VERSION 5.7 ;
  NOWIREEXTENSIONATPIN ON ;
  DIVIDERCHAR "/" ;
  BUSBITCHARS "[]" ;
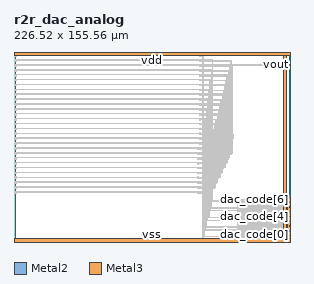
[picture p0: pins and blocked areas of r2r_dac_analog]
MACRO r2r_dac_analog
  CLASS BLOCK ;
  FOREIGN r2r_dac_analog ;
  ORIGIN 0.000 0.000 ;
  SIZE 226.520 BY 155.560 ;
  PIN dac_code[7]
    DIRECTION INPUT ;
    USE SIGNAL ;
    ANTENNAGATEAREA 11.020000 ;
    PORT
      LAYER Metal2 ;
        RECT 225.320 32.415 226.520 32.815 ;
    END
  END dac_code[7]
  PIN dac_code[6]
    DIRECTION INPUT ;
    USE SIGNAL ;
    ANTENNAGATEAREA 11.020000 ;
    PORT
      LAYER Metal2 ;
        RECT 225.320 28.465 226.520 28.865 ;
    END
  END dac_code[6]
  PIN dac_code[5]
    DIRECTION INPUT ;
    USE SIGNAL ;
    ANTENNAGATEAREA 11.020000 ;
    PORT
      LAYER Metal2 ;
        RECT 225.320 24.575 226.520 24.975 ;
    END
  END dac_code[5]
  PIN dac_code[4]
    DIRECTION INPUT ;
    USE SIGNAL ;
    ANTENNAGATEAREA 11.020000 ;
    PORT
      LAYER Metal2 ;
        RECT 225.320 20.625 226.520 21.025 ;
    END
  END dac_code[4]
  PIN dac_code[3]
    DIRECTION INPUT ;
    USE SIGNAL ;
    ANTENNAGATEAREA 11.020000 ;
    PORT
      LAYER Metal2 ;
        RECT 225.320 16.735 226.520 17.135 ;
    END
  END dac_code[3]
  PIN dac_code[2]
    DIRECTION INPUT ;
    USE SIGNAL ;
    ANTENNAGATEAREA 11.020000 ;
    PORT
      LAYER Metal2 ;
        RECT 225.320 12.785 226.520 13.185 ;
    END
  END dac_code[2]
  PIN dac_code[1]
    DIRECTION INPUT ;
    USE SIGNAL ;
    ANTENNAGATEAREA 11.020000 ;
    PORT
      LAYER Metal2 ;
        RECT 225.320 8.895 226.520 9.295 ;
    END
  END dac_code[1]
  PIN dac_code[0]
    DIRECTION INPUT ;
    USE SIGNAL ;
    ANTENNAGATEAREA 11.020000 ;
    PORT
      LAYER Metal2 ;
        RECT 225.320 4.945 226.520 5.345 ;
    END
  END dac_code[0]
  PIN vout
    DIRECTION INOUT ;
    USE SIGNAL ;
    PORT
      LAYER Metal2 ;
        RECT 225.320 144.810 226.520 145.210 ;
    END
  END vout
  PIN vdd
    DIRECTION INOUT ;
    USE POWER ;
    PORT
      LAYER Metal3 ;
        RECT 0.000 152.760 226.520 155.560 ;
    END
    PORT
      LAYER Metal3 ;
        RECT 220.520 6.320 223.220 152.760 ;
    END
  END vdd
  PIN vss
    DIRECTION INOUT ;
    USE GROUND ;
    PORT
      LAYER Metal3 ;
        RECT 0.000 0.000 226.520 2.800 ;
    END
    PORT
      LAYER Metal3 ;
        RECT 223.520 2.800 226.520 35.360 ;
    END
  END vss
  OBS
      LAYER Pwell ;
        RECT 183.130 32.800 220.950 34.990 ;
      LAYER Nwell ;
        RECT 183.130 28.480 220.950 32.800 ;
      LAYER Pwell ;
        RECT 183.130 24.960 220.950 28.480 ;
      LAYER Nwell ;
        RECT 183.130 20.640 220.950 24.960 ;
      LAYER Pwell ;
        RECT 183.130 17.120 220.950 20.640 ;
      LAYER Nwell ;
        RECT 183.130 12.800 220.950 17.120 ;
      LAYER Pwell ;
        RECT 183.130 9.280 220.950 12.800 ;
      LAYER Nwell ;
        RECT 183.130 4.960 220.950 9.280 ;
      LAYER Pwell ;
        RECT 183.130 2.770 220.950 4.960 ;
      LAYER Metal1 ;
        RECT 0.150 1.200 0.530 155.560 ;
        RECT 1.520 153.210 1.900 153.260 ;
        RECT 1.510 152.810 1.910 153.210 ;
        RECT 1.520 151.860 1.900 152.810 ;
        RECT 152.180 152.310 152.560 153.260 ;
        RECT 152.170 151.910 152.570 152.310 ;
        RECT 152.180 151.860 152.560 151.910 ;
        RECT 1.520 149.210 1.900 149.260 ;
        RECT 1.510 148.810 1.910 149.210 ;
        RECT 1.520 147.860 1.900 148.810 ;
        RECT 152.180 148.310 152.560 149.260 ;
        RECT 152.170 147.910 152.570 148.310 ;
        RECT 152.180 147.860 152.560 147.910 ;
        RECT 1.520 145.210 1.900 145.260 ;
        RECT 1.510 144.810 1.910 145.210 ;
        RECT 1.520 143.860 1.900 144.810 ;
        RECT 152.180 144.310 152.560 145.260 ;
        RECT 152.170 143.910 152.570 144.310 ;
        RECT 152.180 143.860 152.560 143.910 ;
        RECT 1.520 141.210 1.900 141.260 ;
        RECT 1.510 140.810 1.910 141.210 ;
        RECT 1.520 139.860 1.900 140.810 ;
        RECT 152.180 140.310 152.560 141.260 ;
        RECT 152.170 139.910 152.570 140.310 ;
        RECT 152.180 139.860 152.560 139.910 ;
        RECT 1.520 137.210 1.900 137.260 ;
        RECT 1.510 136.810 1.910 137.210 ;
        RECT 1.520 135.860 1.900 136.810 ;
        RECT 152.180 136.310 152.560 137.260 ;
        RECT 152.170 135.910 152.570 136.310 ;
        RECT 152.180 135.860 152.560 135.910 ;
        RECT 1.520 133.210 1.900 133.260 ;
        RECT 1.510 132.810 1.910 133.210 ;
        RECT 1.520 131.860 1.900 132.810 ;
        RECT 152.180 132.310 152.560 133.260 ;
        RECT 152.170 131.910 152.570 132.310 ;
        RECT 152.180 131.860 152.560 131.910 ;
        RECT 1.520 129.210 1.900 129.260 ;
        RECT 1.510 128.810 1.910 129.210 ;
        RECT 1.520 127.860 1.900 128.810 ;
        RECT 152.180 128.310 152.560 129.260 ;
        RECT 152.170 127.910 152.570 128.310 ;
        RECT 152.180 127.860 152.560 127.910 ;
        RECT 1.520 125.210 1.900 125.260 ;
        RECT 1.510 124.810 1.910 125.210 ;
        RECT 1.520 123.860 1.900 124.810 ;
        RECT 152.180 124.310 152.560 125.260 ;
        RECT 152.170 123.910 152.570 124.310 ;
        RECT 152.180 123.860 152.560 123.910 ;
        RECT 1.520 121.210 1.900 121.260 ;
        RECT 1.510 120.810 1.910 121.210 ;
        RECT 1.520 119.860 1.900 120.810 ;
        RECT 152.180 120.310 152.560 121.260 ;
        RECT 152.170 119.910 152.570 120.310 ;
        RECT 152.180 119.860 152.560 119.910 ;
        RECT 1.520 117.210 1.900 117.260 ;
        RECT 1.510 116.810 1.910 117.210 ;
        RECT 1.520 115.860 1.900 116.810 ;
        RECT 152.180 116.310 152.560 117.260 ;
        RECT 152.170 115.910 152.570 116.310 ;
        RECT 152.180 115.860 152.560 115.910 ;
        RECT 1.520 113.210 1.900 113.260 ;
        RECT 1.510 112.810 1.910 113.210 ;
        RECT 1.520 111.860 1.900 112.810 ;
        RECT 152.180 112.310 152.560 113.260 ;
        RECT 152.170 111.910 152.570 112.310 ;
        RECT 152.180 111.860 152.560 111.910 ;
        RECT 1.520 109.210 1.900 109.260 ;
        RECT 1.510 108.810 1.910 109.210 ;
        RECT 1.520 107.860 1.900 108.810 ;
        RECT 152.180 108.310 152.560 109.260 ;
        RECT 152.170 107.910 152.570 108.310 ;
        RECT 152.180 107.860 152.560 107.910 ;
        RECT 1.520 105.210 1.900 105.260 ;
        RECT 1.510 104.810 1.910 105.210 ;
        RECT 1.520 103.860 1.900 104.810 ;
        RECT 152.180 104.310 152.560 105.260 ;
        RECT 152.170 103.910 152.570 104.310 ;
        RECT 152.180 103.860 152.560 103.910 ;
        RECT 1.520 101.210 1.900 101.260 ;
        RECT 1.510 100.810 1.910 101.210 ;
        RECT 1.520 99.860 1.900 100.810 ;
        RECT 152.180 100.310 152.560 101.260 ;
        RECT 152.170 99.910 152.570 100.310 ;
        RECT 152.180 99.860 152.560 99.910 ;
        RECT 1.520 97.210 1.900 97.260 ;
        RECT 1.510 96.810 1.910 97.210 ;
        RECT 1.520 95.860 1.900 96.810 ;
        RECT 152.180 96.310 152.560 97.260 ;
        RECT 152.170 95.910 152.570 96.310 ;
        RECT 152.180 95.860 152.560 95.910 ;
        RECT 1.520 93.210 1.900 93.260 ;
        RECT 1.510 92.810 1.910 93.210 ;
        RECT 1.520 91.860 1.900 92.810 ;
        RECT 152.180 92.310 152.560 93.260 ;
        RECT 152.170 91.910 152.570 92.310 ;
        RECT 152.180 91.860 152.560 91.910 ;
        RECT 1.520 89.210 1.900 89.260 ;
        RECT 1.510 88.810 1.910 89.210 ;
        RECT 1.520 87.860 1.900 88.810 ;
        RECT 152.180 88.310 152.560 89.260 ;
        RECT 152.170 87.910 152.570 88.310 ;
        RECT 152.180 87.860 152.560 87.910 ;
        RECT 1.520 85.210 1.900 85.260 ;
        RECT 1.510 84.810 1.910 85.210 ;
        RECT 1.520 83.860 1.900 84.810 ;
        RECT 152.180 84.310 152.560 85.260 ;
        RECT 152.170 83.910 152.570 84.310 ;
        RECT 152.180 83.860 152.560 83.910 ;
        RECT 1.520 81.210 1.900 81.260 ;
        RECT 1.510 80.810 1.910 81.210 ;
        RECT 1.520 79.860 1.900 80.810 ;
        RECT 152.180 80.310 152.560 81.260 ;
        RECT 152.170 79.910 152.570 80.310 ;
        RECT 152.180 79.860 152.560 79.910 ;
        RECT 1.520 77.210 1.900 77.260 ;
        RECT 1.510 76.810 1.910 77.210 ;
        RECT 1.520 75.860 1.900 76.810 ;
        RECT 150.540 76.310 150.920 77.260 ;
        RECT 150.530 75.910 150.930 76.310 ;
        RECT 150.540 75.860 150.920 75.910 ;
        RECT 1.520 73.210 1.900 73.260 ;
        RECT 1.510 72.810 1.910 73.210 ;
        RECT 1.520 71.860 1.900 72.810 ;
        RECT 150.540 72.310 150.920 73.260 ;
        RECT 150.530 71.910 150.930 72.310 ;
        RECT 150.540 71.860 150.920 71.910 ;
        RECT 1.520 69.210 1.900 69.260 ;
        RECT 1.510 68.810 1.910 69.210 ;
        RECT 1.520 67.860 1.900 68.810 ;
        RECT 150.540 68.310 150.920 69.260 ;
        RECT 150.530 67.910 150.930 68.310 ;
        RECT 150.540 67.860 150.920 67.910 ;
        RECT 1.520 65.210 1.900 65.260 ;
        RECT 1.510 64.810 1.910 65.210 ;
        RECT 1.520 63.860 1.900 64.810 ;
        RECT 150.540 64.310 150.920 65.260 ;
        RECT 150.530 63.910 150.930 64.310 ;
        RECT 150.540 63.860 150.920 63.910 ;
        RECT 1.520 61.210 1.900 61.260 ;
        RECT 1.510 60.810 1.910 61.210 ;
        RECT 1.520 59.860 1.900 60.810 ;
        RECT 150.540 60.310 150.920 61.260 ;
        RECT 150.530 59.910 150.930 60.310 ;
        RECT 150.540 59.860 150.920 59.910 ;
        RECT 1.520 57.210 1.900 57.260 ;
        RECT 1.510 56.810 1.910 57.210 ;
        RECT 1.520 55.860 1.900 56.810 ;
        RECT 150.540 56.310 150.920 57.260 ;
        RECT 150.530 55.910 150.930 56.310 ;
        RECT 150.540 55.860 150.920 55.910 ;
        RECT 1.520 53.210 1.900 53.260 ;
        RECT 1.510 52.810 1.910 53.210 ;
        RECT 1.520 51.860 1.900 52.810 ;
        RECT 150.540 52.310 150.920 53.260 ;
        RECT 150.530 51.910 150.930 52.310 ;
        RECT 150.540 51.860 150.920 51.910 ;
        RECT 1.520 49.210 1.900 49.260 ;
        RECT 1.510 48.810 1.910 49.210 ;
        RECT 1.520 47.860 1.900 48.810 ;
        RECT 150.540 48.310 150.920 49.260 ;
        RECT 150.530 47.910 150.930 48.310 ;
        RECT 150.540 47.860 150.920 47.910 ;
        RECT 1.520 45.210 1.900 45.260 ;
        RECT 1.510 44.810 1.910 45.210 ;
        RECT 1.520 43.860 1.900 44.810 ;
        RECT 150.540 44.310 150.920 45.260 ;
        RECT 150.530 43.910 150.930 44.310 ;
        RECT 150.540 43.860 150.920 43.910 ;
        RECT 1.520 41.210 1.900 41.260 ;
        RECT 1.510 40.810 1.910 41.210 ;
        RECT 1.520 39.860 1.900 40.810 ;
        RECT 150.540 40.310 150.920 41.260 ;
        RECT 150.530 39.910 150.930 40.310 ;
        RECT 150.540 39.860 150.920 39.910 ;
        RECT 0.140 0.000 0.540 1.200 ;
        RECT 154.360 0.000 154.760 153.210 ;
        RECT 155.360 4.100 155.760 93.210 ;
        RECT 156.360 9.740 156.760 101.210 ;
        RECT 157.360 11.940 157.760 109.210 ;
        RECT 158.360 17.580 158.760 117.210 ;
        RECT 159.360 19.780 159.760 125.210 ;
        RECT 160.360 25.420 160.760 133.210 ;
        RECT 161.360 27.620 161.760 141.210 ;
        RECT 162.360 33.260 162.760 149.210 ;
        RECT 163.360 43.910 163.760 92.310 ;
        RECT 164.360 44.810 164.760 96.310 ;
        RECT 165.360 47.910 165.760 100.310 ;
        RECT 166.360 48.810 166.760 104.310 ;
        RECT 167.360 51.910 167.760 108.310 ;
        RECT 168.360 52.810 168.760 112.310 ;
        RECT 169.360 55.910 169.760 116.310 ;
        RECT 170.360 56.810 170.760 120.310 ;
        RECT 171.360 59.910 171.760 124.310 ;
        RECT 172.360 60.810 172.760 128.310 ;
        RECT 173.360 63.910 173.760 132.310 ;
        RECT 174.360 64.810 174.760 136.310 ;
        RECT 175.360 67.910 175.760 140.310 ;
        RECT 176.360 68.810 176.760 144.310 ;
        RECT 177.360 71.910 177.760 148.310 ;
        RECT 178.360 72.810 178.760 145.210 ;
        RECT 220.920 144.810 225.720 145.210 ;
        RECT 179.360 84.810 179.760 88.310 ;
        RECT 219.400 34.860 226.220 35.360 ;
        RECT 183.560 34.260 226.220 34.860 ;
        RECT 183.950 33.375 184.290 34.260 ;
        RECT 184.925 33.400 185.155 34.260 ;
        RECT 186.045 33.370 186.275 33.885 ;
        RECT 187.165 33.600 187.395 34.260 ;
        RECT 188.285 33.370 188.515 33.885 ;
        RECT 189.405 33.600 189.635 34.260 ;
        RECT 190.525 33.370 190.755 33.885 ;
        RECT 191.645 33.600 191.875 34.260 ;
        RECT 192.765 33.370 192.995 33.885 ;
        RECT 193.885 33.600 194.115 34.260 ;
        RECT 195.005 33.370 195.360 33.885 ;
        RECT 196.125 33.600 196.355 34.260 ;
        RECT 198.310 33.925 198.650 34.260 ;
        RECT 200.550 33.925 200.890 34.260 ;
        RECT 202.790 33.925 203.130 34.260 ;
        RECT 205.030 33.925 205.370 34.260 ;
        RECT 207.270 33.925 207.610 34.260 ;
        RECT 209.510 33.925 209.850 34.260 ;
        RECT 211.750 33.925 212.090 34.260 ;
        RECT 213.990 33.925 214.330 34.260 ;
        RECT 216.230 33.925 216.570 34.260 ;
        RECT 197.245 33.695 197.505 33.885 ;
        RECT 199.485 33.695 199.715 33.885 ;
        RECT 201.725 33.695 201.955 33.885 ;
        RECT 203.965 33.695 204.195 33.885 ;
        RECT 206.205 33.695 206.435 33.885 ;
        RECT 208.445 33.695 208.675 33.885 ;
        RECT 210.685 33.695 210.915 33.885 ;
        RECT 212.925 33.695 213.155 33.885 ;
        RECT 215.165 33.695 215.395 33.885 ;
        RECT 217.405 33.695 217.635 33.885 ;
        RECT 186.045 33.140 195.360 33.370 ;
        RECT 194.905 32.820 195.360 33.140 ;
        RECT 197.245 33.050 217.635 33.695 ;
        RECT 218.525 33.400 218.755 34.260 ;
        RECT 219.400 33.760 226.220 34.260 ;
        RECT 219.790 33.375 220.130 33.760 ;
        RECT 183.950 30.940 184.290 32.630 ;
        RECT 185.310 32.410 194.580 32.820 ;
        RECT 194.905 32.590 206.250 32.820 ;
        RECT 194.905 32.030 195.360 32.590 ;
        RECT 206.910 32.290 207.810 33.050 ;
        RECT 208.360 32.590 218.280 32.820 ;
        RECT 184.925 30.940 185.155 32.030 ;
        RECT 186.045 31.800 195.360 32.030 ;
        RECT 186.045 31.180 186.275 31.800 ;
        RECT 187.065 30.940 187.295 31.560 ;
        RECT 188.185 31.180 188.415 31.800 ;
        RECT 189.305 30.940 189.535 31.560 ;
        RECT 190.425 31.180 190.655 31.800 ;
        RECT 191.545 30.940 191.775 31.560 ;
        RECT 192.665 31.180 192.895 31.800 ;
        RECT 193.785 30.940 194.015 31.560 ;
        RECT 194.905 31.180 195.360 31.800 ;
        RECT 196.025 30.940 196.255 32.030 ;
        RECT 197.245 31.560 217.535 32.290 ;
        RECT 197.245 31.180 197.475 31.560 ;
        RECT 198.265 30.940 198.495 31.330 ;
        RECT 199.385 31.180 199.615 31.560 ;
        RECT 200.505 30.940 200.735 31.330 ;
        RECT 201.625 31.180 201.855 31.560 ;
        RECT 202.745 30.940 202.975 31.330 ;
        RECT 203.865 31.180 204.095 31.560 ;
        RECT 204.985 30.940 205.215 31.330 ;
        RECT 206.105 31.180 206.335 31.560 ;
        RECT 207.225 30.940 207.455 31.330 ;
        RECT 208.345 31.180 208.575 31.560 ;
        RECT 209.465 30.940 209.695 31.330 ;
        RECT 210.585 31.180 210.815 31.560 ;
        RECT 211.705 30.940 211.935 31.330 ;
        RECT 212.825 31.180 213.055 31.560 ;
        RECT 213.945 30.940 214.175 31.330 ;
        RECT 215.065 31.180 215.295 31.560 ;
        RECT 216.185 30.940 216.415 31.330 ;
        RECT 217.305 31.180 217.535 31.560 ;
        RECT 218.425 30.940 218.655 32.030 ;
        RECT 219.790 31.440 220.130 32.630 ;
        RECT 220.920 32.415 225.720 32.815 ;
        RECT 219.400 30.940 226.220 31.440 ;
        RECT 183.560 30.340 226.220 30.940 ;
        RECT 183.950 28.650 184.290 30.340 ;
        RECT 184.925 29.250 185.155 30.340 ;
        RECT 186.045 29.480 186.275 30.100 ;
        RECT 187.065 29.720 187.295 30.340 ;
        RECT 188.185 29.480 188.415 30.100 ;
        RECT 189.305 29.720 189.535 30.340 ;
        RECT 190.425 29.480 190.655 30.100 ;
        RECT 191.545 29.720 191.775 30.340 ;
        RECT 192.665 29.480 192.895 30.100 ;
        RECT 193.785 29.720 194.015 30.340 ;
        RECT 194.905 29.480 195.360 30.100 ;
        RECT 186.045 29.250 195.360 29.480 ;
        RECT 196.025 29.250 196.255 30.340 ;
        RECT 197.245 29.720 197.475 30.100 ;
        RECT 198.265 29.950 198.495 30.340 ;
        RECT 199.385 29.720 199.615 30.100 ;
        RECT 200.505 29.950 200.735 30.340 ;
        RECT 201.625 29.720 201.855 30.100 ;
        RECT 202.745 29.950 202.975 30.340 ;
        RECT 203.865 29.720 204.095 30.100 ;
        RECT 204.985 29.950 205.215 30.340 ;
        RECT 206.105 29.720 206.335 30.100 ;
        RECT 207.225 29.950 207.455 30.340 ;
        RECT 208.345 29.720 208.575 30.100 ;
        RECT 209.465 29.950 209.695 30.340 ;
        RECT 210.585 29.720 210.815 30.100 ;
        RECT 211.705 29.950 211.935 30.340 ;
        RECT 212.825 29.720 213.055 30.100 ;
        RECT 213.945 29.950 214.175 30.340 ;
        RECT 215.065 29.720 215.295 30.100 ;
        RECT 216.185 29.950 216.415 30.340 ;
        RECT 217.305 29.720 217.535 30.100 ;
        RECT 185.310 28.460 194.580 28.870 ;
        RECT 194.905 28.690 195.360 29.250 ;
        RECT 197.245 28.990 217.535 29.720 ;
        RECT 218.425 29.250 218.655 30.340 ;
        RECT 219.400 29.840 226.220 30.340 ;
        RECT 194.905 28.460 206.250 28.690 ;
        RECT 194.905 28.140 195.360 28.460 ;
        RECT 206.910 28.230 207.810 28.990 ;
        RECT 208.360 28.460 218.280 28.690 ;
        RECT 219.790 28.650 220.130 29.840 ;
        RECT 220.920 28.465 225.720 28.865 ;
        RECT 186.045 27.910 195.360 28.140 ;
        RECT 183.950 27.020 184.290 27.905 ;
        RECT 184.925 27.020 185.155 27.880 ;
        RECT 186.045 27.395 186.275 27.910 ;
        RECT 187.165 27.020 187.395 27.680 ;
        RECT 188.285 27.395 188.515 27.910 ;
        RECT 189.405 27.020 189.635 27.680 ;
        RECT 190.525 27.395 190.755 27.910 ;
        RECT 191.645 27.020 191.875 27.680 ;
        RECT 192.765 27.395 192.995 27.910 ;
        RECT 193.885 27.020 194.115 27.680 ;
        RECT 195.005 27.395 195.360 27.910 ;
        RECT 196.125 27.020 196.355 27.680 ;
        RECT 197.245 27.585 217.635 28.230 ;
        RECT 197.245 27.395 197.505 27.585 ;
        RECT 199.485 27.395 199.715 27.585 ;
        RECT 201.725 27.395 201.955 27.585 ;
        RECT 203.965 27.395 204.195 27.585 ;
        RECT 206.205 27.395 206.435 27.585 ;
        RECT 208.445 27.395 208.675 27.585 ;
        RECT 210.685 27.395 210.915 27.585 ;
        RECT 212.925 27.395 213.155 27.585 ;
        RECT 215.165 27.395 215.395 27.585 ;
        RECT 217.405 27.395 217.635 27.585 ;
        RECT 198.310 27.020 198.650 27.355 ;
        RECT 200.550 27.020 200.890 27.355 ;
        RECT 202.790 27.020 203.130 27.355 ;
        RECT 205.030 27.020 205.370 27.355 ;
        RECT 207.270 27.020 207.610 27.355 ;
        RECT 209.510 27.020 209.850 27.355 ;
        RECT 211.750 27.020 212.090 27.355 ;
        RECT 213.990 27.020 214.330 27.355 ;
        RECT 216.230 27.020 216.570 27.355 ;
        RECT 218.525 27.020 218.755 27.880 ;
        RECT 219.790 27.520 220.130 27.905 ;
        RECT 219.400 27.020 226.220 27.520 ;
        RECT 183.560 26.420 226.220 27.020 ;
        RECT 183.950 25.535 184.290 26.420 ;
        RECT 184.925 25.560 185.155 26.420 ;
        RECT 186.045 25.530 186.275 26.045 ;
        RECT 187.165 25.760 187.395 26.420 ;
        RECT 188.285 25.530 188.515 26.045 ;
        RECT 189.405 25.760 189.635 26.420 ;
        RECT 190.525 25.530 190.755 26.045 ;
        RECT 191.645 25.760 191.875 26.420 ;
        RECT 192.765 25.530 192.995 26.045 ;
        RECT 193.885 25.760 194.115 26.420 ;
        RECT 195.005 25.530 195.360 26.045 ;
        RECT 196.125 25.760 196.355 26.420 ;
        RECT 198.310 26.085 198.650 26.420 ;
        RECT 200.550 26.085 200.890 26.420 ;
        RECT 202.790 26.085 203.130 26.420 ;
        RECT 205.030 26.085 205.370 26.420 ;
        RECT 207.270 26.085 207.610 26.420 ;
        RECT 209.510 26.085 209.850 26.420 ;
        RECT 211.750 26.085 212.090 26.420 ;
        RECT 213.990 26.085 214.330 26.420 ;
        RECT 216.230 26.085 216.570 26.420 ;
        RECT 197.245 25.855 197.505 26.045 ;
        RECT 199.485 25.855 199.715 26.045 ;
        RECT 201.725 25.855 201.955 26.045 ;
        RECT 203.965 25.855 204.195 26.045 ;
        RECT 206.205 25.855 206.435 26.045 ;
        RECT 208.445 25.855 208.675 26.045 ;
        RECT 210.685 25.855 210.915 26.045 ;
        RECT 212.925 25.855 213.155 26.045 ;
        RECT 215.165 25.855 215.395 26.045 ;
        RECT 217.405 25.855 217.635 26.045 ;
        RECT 186.045 25.300 195.360 25.530 ;
        RECT 194.905 24.980 195.360 25.300 ;
        RECT 197.245 25.210 217.635 25.855 ;
        RECT 218.525 25.560 218.755 26.420 ;
        RECT 219.400 25.920 226.220 26.420 ;
        RECT 219.790 25.535 220.130 25.920 ;
        RECT 183.950 23.100 184.290 24.790 ;
        RECT 185.310 24.570 194.580 24.980 ;
        RECT 194.905 24.750 206.250 24.980 ;
        RECT 194.905 24.190 195.360 24.750 ;
        RECT 206.910 24.450 207.810 25.210 ;
        RECT 208.360 24.750 218.280 24.980 ;
        RECT 184.925 23.100 185.155 24.190 ;
        RECT 186.045 23.960 195.360 24.190 ;
        RECT 186.045 23.340 186.275 23.960 ;
        RECT 187.065 23.100 187.295 23.720 ;
        RECT 188.185 23.340 188.415 23.960 ;
        RECT 189.305 23.100 189.535 23.720 ;
        RECT 190.425 23.340 190.655 23.960 ;
        RECT 191.545 23.100 191.775 23.720 ;
        RECT 192.665 23.340 192.895 23.960 ;
        RECT 193.785 23.100 194.015 23.720 ;
        RECT 194.905 23.340 195.360 23.960 ;
        RECT 196.025 23.100 196.255 24.190 ;
        RECT 197.245 23.720 217.535 24.450 ;
        RECT 197.245 23.340 197.475 23.720 ;
        RECT 198.265 23.100 198.495 23.490 ;
        RECT 199.385 23.340 199.615 23.720 ;
        RECT 200.505 23.100 200.735 23.490 ;
        RECT 201.625 23.340 201.855 23.720 ;
        RECT 202.745 23.100 202.975 23.490 ;
        RECT 203.865 23.340 204.095 23.720 ;
        RECT 204.985 23.100 205.215 23.490 ;
        RECT 206.105 23.340 206.335 23.720 ;
        RECT 207.225 23.100 207.455 23.490 ;
        RECT 208.345 23.340 208.575 23.720 ;
        RECT 209.465 23.100 209.695 23.490 ;
        RECT 210.585 23.340 210.815 23.720 ;
        RECT 211.705 23.100 211.935 23.490 ;
        RECT 212.825 23.340 213.055 23.720 ;
        RECT 213.945 23.100 214.175 23.490 ;
        RECT 215.065 23.340 215.295 23.720 ;
        RECT 216.185 23.100 216.415 23.490 ;
        RECT 217.305 23.340 217.535 23.720 ;
        RECT 218.425 23.100 218.655 24.190 ;
        RECT 219.790 23.600 220.130 24.790 ;
        RECT 220.920 24.575 225.720 24.975 ;
        RECT 219.400 23.100 226.220 23.600 ;
        RECT 183.560 22.500 226.220 23.100 ;
        RECT 183.950 20.810 184.290 22.500 ;
        RECT 184.925 21.410 185.155 22.500 ;
        RECT 186.045 21.640 186.275 22.260 ;
        RECT 187.065 21.880 187.295 22.500 ;
        RECT 188.185 21.640 188.415 22.260 ;
        RECT 189.305 21.880 189.535 22.500 ;
        RECT 190.425 21.640 190.655 22.260 ;
        RECT 191.545 21.880 191.775 22.500 ;
        RECT 192.665 21.640 192.895 22.260 ;
        RECT 193.785 21.880 194.015 22.500 ;
        RECT 194.905 21.640 195.360 22.260 ;
        RECT 186.045 21.410 195.360 21.640 ;
        RECT 196.025 21.410 196.255 22.500 ;
        RECT 197.245 21.880 197.475 22.260 ;
        RECT 198.265 22.110 198.495 22.500 ;
        RECT 199.385 21.880 199.615 22.260 ;
        RECT 200.505 22.110 200.735 22.500 ;
        RECT 201.625 21.880 201.855 22.260 ;
        RECT 202.745 22.110 202.975 22.500 ;
        RECT 203.865 21.880 204.095 22.260 ;
        RECT 204.985 22.110 205.215 22.500 ;
        RECT 206.105 21.880 206.335 22.260 ;
        RECT 207.225 22.110 207.455 22.500 ;
        RECT 208.345 21.880 208.575 22.260 ;
        RECT 209.465 22.110 209.695 22.500 ;
        RECT 210.585 21.880 210.815 22.260 ;
        RECT 211.705 22.110 211.935 22.500 ;
        RECT 212.825 21.880 213.055 22.260 ;
        RECT 213.945 22.110 214.175 22.500 ;
        RECT 215.065 21.880 215.295 22.260 ;
        RECT 216.185 22.110 216.415 22.500 ;
        RECT 217.305 21.880 217.535 22.260 ;
        RECT 185.310 20.620 194.580 21.030 ;
        RECT 194.905 20.850 195.360 21.410 ;
        RECT 197.245 21.150 217.535 21.880 ;
        RECT 218.425 21.410 218.655 22.500 ;
        RECT 219.400 22.000 226.220 22.500 ;
        RECT 194.905 20.620 206.250 20.850 ;
        RECT 194.905 20.300 195.360 20.620 ;
        RECT 206.910 20.390 207.810 21.150 ;
        RECT 208.360 20.620 218.280 20.850 ;
        RECT 219.790 20.810 220.130 22.000 ;
        RECT 220.920 20.625 225.720 21.025 ;
        RECT 186.045 20.070 195.360 20.300 ;
        RECT 183.950 19.180 184.290 20.065 ;
        RECT 184.925 19.180 185.155 20.040 ;
        RECT 186.045 19.555 186.275 20.070 ;
        RECT 187.165 19.180 187.395 19.840 ;
        RECT 188.285 19.555 188.515 20.070 ;
        RECT 189.405 19.180 189.635 19.840 ;
        RECT 190.525 19.555 190.755 20.070 ;
        RECT 191.645 19.180 191.875 19.840 ;
        RECT 192.765 19.555 192.995 20.070 ;
        RECT 193.885 19.180 194.115 19.840 ;
        RECT 195.005 19.555 195.360 20.070 ;
        RECT 196.125 19.180 196.355 19.840 ;
        RECT 197.245 19.745 217.635 20.390 ;
        RECT 197.245 19.555 197.505 19.745 ;
        RECT 199.485 19.555 199.715 19.745 ;
        RECT 201.725 19.555 201.955 19.745 ;
        RECT 203.965 19.555 204.195 19.745 ;
        RECT 206.205 19.555 206.435 19.745 ;
        RECT 208.445 19.555 208.675 19.745 ;
        RECT 210.685 19.555 210.915 19.745 ;
        RECT 212.925 19.555 213.155 19.745 ;
        RECT 215.165 19.555 215.395 19.745 ;
        RECT 217.405 19.555 217.635 19.745 ;
        RECT 198.310 19.180 198.650 19.515 ;
        RECT 200.550 19.180 200.890 19.515 ;
        RECT 202.790 19.180 203.130 19.515 ;
        RECT 205.030 19.180 205.370 19.515 ;
        RECT 207.270 19.180 207.610 19.515 ;
        RECT 209.510 19.180 209.850 19.515 ;
        RECT 211.750 19.180 212.090 19.515 ;
        RECT 213.990 19.180 214.330 19.515 ;
        RECT 216.230 19.180 216.570 19.515 ;
        RECT 218.525 19.180 218.755 20.040 ;
        RECT 219.790 19.680 220.130 20.065 ;
        RECT 219.400 19.180 226.220 19.680 ;
        RECT 183.560 18.580 226.220 19.180 ;
        RECT 183.950 17.695 184.290 18.580 ;
        RECT 184.925 17.720 185.155 18.580 ;
        RECT 186.045 17.690 186.275 18.205 ;
        RECT 187.165 17.920 187.395 18.580 ;
        RECT 188.285 17.690 188.515 18.205 ;
        RECT 189.405 17.920 189.635 18.580 ;
        RECT 190.525 17.690 190.755 18.205 ;
        RECT 191.645 17.920 191.875 18.580 ;
        RECT 192.765 17.690 192.995 18.205 ;
        RECT 193.885 17.920 194.115 18.580 ;
        RECT 195.005 17.690 195.360 18.205 ;
        RECT 196.125 17.920 196.355 18.580 ;
        RECT 198.310 18.245 198.650 18.580 ;
        RECT 200.550 18.245 200.890 18.580 ;
        RECT 202.790 18.245 203.130 18.580 ;
        RECT 205.030 18.245 205.370 18.580 ;
        RECT 207.270 18.245 207.610 18.580 ;
        RECT 209.510 18.245 209.850 18.580 ;
        RECT 211.750 18.245 212.090 18.580 ;
        RECT 213.990 18.245 214.330 18.580 ;
        RECT 216.230 18.245 216.570 18.580 ;
        RECT 197.245 18.015 197.505 18.205 ;
        RECT 199.485 18.015 199.715 18.205 ;
        RECT 201.725 18.015 201.955 18.205 ;
        RECT 203.965 18.015 204.195 18.205 ;
        RECT 206.205 18.015 206.435 18.205 ;
        RECT 208.445 18.015 208.675 18.205 ;
        RECT 210.685 18.015 210.915 18.205 ;
        RECT 212.925 18.015 213.155 18.205 ;
        RECT 215.165 18.015 215.395 18.205 ;
        RECT 217.405 18.015 217.635 18.205 ;
        RECT 186.045 17.460 195.360 17.690 ;
        RECT 194.905 17.140 195.360 17.460 ;
        RECT 197.245 17.370 217.635 18.015 ;
        RECT 218.525 17.720 218.755 18.580 ;
        RECT 219.400 18.080 226.220 18.580 ;
        RECT 219.790 17.695 220.130 18.080 ;
        RECT 183.950 15.260 184.290 16.950 ;
        RECT 185.310 16.730 194.580 17.140 ;
        RECT 194.905 16.910 206.250 17.140 ;
        RECT 194.905 16.350 195.360 16.910 ;
        RECT 206.910 16.610 207.810 17.370 ;
        RECT 208.360 16.910 218.280 17.140 ;
        RECT 184.925 15.260 185.155 16.350 ;
        RECT 186.045 16.120 195.360 16.350 ;
        RECT 186.045 15.500 186.275 16.120 ;
        RECT 187.065 15.260 187.295 15.880 ;
        RECT 188.185 15.500 188.415 16.120 ;
        RECT 189.305 15.260 189.535 15.880 ;
        RECT 190.425 15.500 190.655 16.120 ;
        RECT 191.545 15.260 191.775 15.880 ;
        RECT 192.665 15.500 192.895 16.120 ;
        RECT 193.785 15.260 194.015 15.880 ;
        RECT 194.905 15.500 195.360 16.120 ;
        RECT 196.025 15.260 196.255 16.350 ;
        RECT 197.245 15.880 217.535 16.610 ;
        RECT 197.245 15.500 197.475 15.880 ;
        RECT 198.265 15.260 198.495 15.650 ;
        RECT 199.385 15.500 199.615 15.880 ;
        RECT 200.505 15.260 200.735 15.650 ;
        RECT 201.625 15.500 201.855 15.880 ;
        RECT 202.745 15.260 202.975 15.650 ;
        RECT 203.865 15.500 204.095 15.880 ;
        RECT 204.985 15.260 205.215 15.650 ;
        RECT 206.105 15.500 206.335 15.880 ;
        RECT 207.225 15.260 207.455 15.650 ;
        RECT 208.345 15.500 208.575 15.880 ;
        RECT 209.465 15.260 209.695 15.650 ;
        RECT 210.585 15.500 210.815 15.880 ;
        RECT 211.705 15.260 211.935 15.650 ;
        RECT 212.825 15.500 213.055 15.880 ;
        RECT 213.945 15.260 214.175 15.650 ;
        RECT 215.065 15.500 215.295 15.880 ;
        RECT 216.185 15.260 216.415 15.650 ;
        RECT 217.305 15.500 217.535 15.880 ;
        RECT 218.425 15.260 218.655 16.350 ;
        RECT 219.790 15.760 220.130 16.950 ;
        RECT 220.920 16.735 225.720 17.135 ;
        RECT 219.400 15.260 226.220 15.760 ;
        RECT 183.560 14.660 226.220 15.260 ;
        RECT 183.950 12.970 184.290 14.660 ;
        RECT 184.925 13.570 185.155 14.660 ;
        RECT 186.045 13.800 186.275 14.420 ;
        RECT 187.065 14.040 187.295 14.660 ;
        RECT 188.185 13.800 188.415 14.420 ;
        RECT 189.305 14.040 189.535 14.660 ;
        RECT 190.425 13.800 190.655 14.420 ;
        RECT 191.545 14.040 191.775 14.660 ;
        RECT 192.665 13.800 192.895 14.420 ;
        RECT 193.785 14.040 194.015 14.660 ;
        RECT 194.905 13.800 195.360 14.420 ;
        RECT 186.045 13.570 195.360 13.800 ;
        RECT 196.025 13.570 196.255 14.660 ;
        RECT 197.245 14.040 197.475 14.420 ;
        RECT 198.265 14.270 198.495 14.660 ;
        RECT 199.385 14.040 199.615 14.420 ;
        RECT 200.505 14.270 200.735 14.660 ;
        RECT 201.625 14.040 201.855 14.420 ;
        RECT 202.745 14.270 202.975 14.660 ;
        RECT 203.865 14.040 204.095 14.420 ;
        RECT 204.985 14.270 205.215 14.660 ;
        RECT 206.105 14.040 206.335 14.420 ;
        RECT 207.225 14.270 207.455 14.660 ;
        RECT 208.345 14.040 208.575 14.420 ;
        RECT 209.465 14.270 209.695 14.660 ;
        RECT 210.585 14.040 210.815 14.420 ;
        RECT 211.705 14.270 211.935 14.660 ;
        RECT 212.825 14.040 213.055 14.420 ;
        RECT 213.945 14.270 214.175 14.660 ;
        RECT 215.065 14.040 215.295 14.420 ;
        RECT 216.185 14.270 216.415 14.660 ;
        RECT 217.305 14.040 217.535 14.420 ;
        RECT 185.310 12.780 194.580 13.190 ;
        RECT 194.905 13.010 195.360 13.570 ;
        RECT 197.245 13.310 217.535 14.040 ;
        RECT 218.425 13.570 218.655 14.660 ;
        RECT 219.400 14.160 226.220 14.660 ;
        RECT 194.905 12.780 206.250 13.010 ;
        RECT 194.905 12.460 195.360 12.780 ;
        RECT 206.910 12.550 207.810 13.310 ;
        RECT 208.360 12.780 218.280 13.010 ;
        RECT 219.790 12.970 220.130 14.160 ;
        RECT 220.920 12.785 225.720 13.185 ;
        RECT 186.045 12.230 195.360 12.460 ;
        RECT 183.950 11.340 184.290 12.225 ;
        RECT 184.925 11.340 185.155 12.200 ;
        RECT 186.045 11.715 186.275 12.230 ;
        RECT 187.165 11.340 187.395 12.000 ;
        RECT 188.285 11.715 188.515 12.230 ;
        RECT 189.405 11.340 189.635 12.000 ;
        RECT 190.525 11.715 190.755 12.230 ;
        RECT 191.645 11.340 191.875 12.000 ;
        RECT 192.765 11.715 192.995 12.230 ;
        RECT 193.885 11.340 194.115 12.000 ;
        RECT 195.005 11.715 195.360 12.230 ;
        RECT 196.125 11.340 196.355 12.000 ;
        RECT 197.245 11.905 217.635 12.550 ;
        RECT 197.245 11.715 197.505 11.905 ;
        RECT 199.485 11.715 199.715 11.905 ;
        RECT 201.725 11.715 201.955 11.905 ;
        RECT 203.965 11.715 204.195 11.905 ;
        RECT 206.205 11.715 206.435 11.905 ;
        RECT 208.445 11.715 208.675 11.905 ;
        RECT 210.685 11.715 210.915 11.905 ;
        RECT 212.925 11.715 213.155 11.905 ;
        RECT 215.165 11.715 215.395 11.905 ;
        RECT 217.405 11.715 217.635 11.905 ;
        RECT 198.310 11.340 198.650 11.675 ;
        RECT 200.550 11.340 200.890 11.675 ;
        RECT 202.790 11.340 203.130 11.675 ;
        RECT 205.030 11.340 205.370 11.675 ;
        RECT 207.270 11.340 207.610 11.675 ;
        RECT 209.510 11.340 209.850 11.675 ;
        RECT 211.750 11.340 212.090 11.675 ;
        RECT 213.990 11.340 214.330 11.675 ;
        RECT 216.230 11.340 216.570 11.675 ;
        RECT 218.525 11.340 218.755 12.200 ;
        RECT 219.790 11.840 220.130 12.225 ;
        RECT 219.400 11.340 226.220 11.840 ;
        RECT 183.560 10.740 226.220 11.340 ;
        RECT 183.950 9.855 184.290 10.740 ;
        RECT 184.925 9.880 185.155 10.740 ;
        RECT 186.045 9.850 186.275 10.365 ;
        RECT 187.165 10.080 187.395 10.740 ;
        RECT 188.285 9.850 188.515 10.365 ;
        RECT 189.405 10.080 189.635 10.740 ;
        RECT 190.525 9.850 190.755 10.365 ;
        RECT 191.645 10.080 191.875 10.740 ;
        RECT 192.765 9.850 192.995 10.365 ;
        RECT 193.885 10.080 194.115 10.740 ;
        RECT 195.005 9.850 195.360 10.365 ;
        RECT 196.125 10.080 196.355 10.740 ;
        RECT 198.310 10.405 198.650 10.740 ;
        RECT 200.550 10.405 200.890 10.740 ;
        RECT 202.790 10.405 203.130 10.740 ;
        RECT 205.030 10.405 205.370 10.740 ;
        RECT 207.270 10.405 207.610 10.740 ;
        RECT 209.510 10.405 209.850 10.740 ;
        RECT 211.750 10.405 212.090 10.740 ;
        RECT 213.990 10.405 214.330 10.740 ;
        RECT 216.230 10.405 216.570 10.740 ;
        RECT 197.245 10.175 197.505 10.365 ;
        RECT 199.485 10.175 199.715 10.365 ;
        RECT 201.725 10.175 201.955 10.365 ;
        RECT 203.965 10.175 204.195 10.365 ;
        RECT 206.205 10.175 206.435 10.365 ;
        RECT 208.445 10.175 208.675 10.365 ;
        RECT 210.685 10.175 210.915 10.365 ;
        RECT 212.925 10.175 213.155 10.365 ;
        RECT 215.165 10.175 215.395 10.365 ;
        RECT 217.405 10.175 217.635 10.365 ;
        RECT 186.045 9.620 195.360 9.850 ;
        RECT 194.905 9.300 195.360 9.620 ;
        RECT 197.245 9.530 217.635 10.175 ;
        RECT 218.525 9.880 218.755 10.740 ;
        RECT 219.400 10.240 226.220 10.740 ;
        RECT 219.790 9.855 220.130 10.240 ;
        RECT 183.950 7.420 184.290 9.110 ;
        RECT 185.310 8.890 194.580 9.300 ;
        RECT 194.905 9.070 206.250 9.300 ;
        RECT 194.905 8.510 195.360 9.070 ;
        RECT 206.910 8.770 207.810 9.530 ;
        RECT 208.360 9.070 218.280 9.300 ;
        RECT 184.925 7.420 185.155 8.510 ;
        RECT 186.045 8.280 195.360 8.510 ;
        RECT 186.045 7.660 186.275 8.280 ;
        RECT 187.065 7.420 187.295 8.040 ;
        RECT 188.185 7.660 188.415 8.280 ;
        RECT 189.305 7.420 189.535 8.040 ;
        RECT 190.425 7.660 190.655 8.280 ;
        RECT 191.545 7.420 191.775 8.040 ;
        RECT 192.665 7.660 192.895 8.280 ;
        RECT 193.785 7.420 194.015 8.040 ;
        RECT 194.905 7.660 195.360 8.280 ;
        RECT 196.025 7.420 196.255 8.510 ;
        RECT 197.245 8.040 217.535 8.770 ;
        RECT 197.245 7.660 197.475 8.040 ;
        RECT 198.265 7.420 198.495 7.810 ;
        RECT 199.385 7.660 199.615 8.040 ;
        RECT 200.505 7.420 200.735 7.810 ;
        RECT 201.625 7.660 201.855 8.040 ;
        RECT 202.745 7.420 202.975 7.810 ;
        RECT 203.865 7.660 204.095 8.040 ;
        RECT 204.985 7.420 205.215 7.810 ;
        RECT 206.105 7.660 206.335 8.040 ;
        RECT 207.225 7.420 207.455 7.810 ;
        RECT 208.345 7.660 208.575 8.040 ;
        RECT 209.465 7.420 209.695 7.810 ;
        RECT 210.585 7.660 210.815 8.040 ;
        RECT 211.705 7.420 211.935 7.810 ;
        RECT 212.825 7.660 213.055 8.040 ;
        RECT 213.945 7.420 214.175 7.810 ;
        RECT 215.065 7.660 215.295 8.040 ;
        RECT 216.185 7.420 216.415 7.810 ;
        RECT 217.305 7.660 217.535 8.040 ;
        RECT 218.425 7.420 218.655 8.510 ;
        RECT 219.790 7.920 220.130 9.110 ;
        RECT 220.920 8.895 225.720 9.295 ;
        RECT 219.400 7.420 226.220 7.920 ;
        RECT 183.560 6.820 226.220 7.420 ;
        RECT 183.950 5.130 184.290 6.820 ;
        RECT 184.925 5.730 185.155 6.820 ;
        RECT 186.045 5.960 186.275 6.580 ;
        RECT 187.065 6.200 187.295 6.820 ;
        RECT 188.185 5.960 188.415 6.580 ;
        RECT 189.305 6.200 189.535 6.820 ;
        RECT 190.425 5.960 190.655 6.580 ;
        RECT 191.545 6.200 191.775 6.820 ;
        RECT 192.665 5.960 192.895 6.580 ;
        RECT 193.785 6.200 194.015 6.820 ;
        RECT 194.905 5.960 195.360 6.580 ;
        RECT 186.045 5.730 195.360 5.960 ;
        RECT 196.025 5.730 196.255 6.820 ;
        RECT 197.245 6.200 197.475 6.580 ;
        RECT 198.265 6.430 198.495 6.820 ;
        RECT 199.385 6.200 199.615 6.580 ;
        RECT 200.505 6.430 200.735 6.820 ;
        RECT 201.625 6.200 201.855 6.580 ;
        RECT 202.745 6.430 202.975 6.820 ;
        RECT 203.865 6.200 204.095 6.580 ;
        RECT 204.985 6.430 205.215 6.820 ;
        RECT 206.105 6.200 206.335 6.580 ;
        RECT 207.225 6.430 207.455 6.820 ;
        RECT 208.345 6.200 208.575 6.580 ;
        RECT 209.465 6.430 209.695 6.820 ;
        RECT 210.585 6.200 210.815 6.580 ;
        RECT 211.705 6.430 211.935 6.820 ;
        RECT 212.825 6.200 213.055 6.580 ;
        RECT 213.945 6.430 214.175 6.820 ;
        RECT 215.065 6.200 215.295 6.580 ;
        RECT 216.185 6.430 216.415 6.820 ;
        RECT 217.305 6.200 217.535 6.580 ;
        RECT 185.310 4.940 194.580 5.350 ;
        RECT 194.905 5.170 195.360 5.730 ;
        RECT 197.245 5.470 217.535 6.200 ;
        RECT 218.425 5.730 218.655 6.820 ;
        RECT 219.400 6.320 226.220 6.820 ;
        RECT 194.905 4.940 206.250 5.170 ;
        RECT 194.905 4.620 195.360 4.940 ;
        RECT 206.910 4.710 207.810 5.470 ;
        RECT 208.360 4.940 218.280 5.170 ;
        RECT 219.790 5.130 220.130 6.320 ;
        RECT 220.920 4.945 225.720 5.345 ;
        RECT 186.045 4.390 195.360 4.620 ;
        RECT 183.950 3.500 184.290 4.385 ;
        RECT 184.925 3.500 185.155 4.360 ;
        RECT 186.045 3.875 186.275 4.390 ;
        RECT 187.165 3.500 187.395 4.160 ;
        RECT 188.285 3.875 188.515 4.390 ;
        RECT 189.405 3.500 189.635 4.160 ;
        RECT 190.525 3.875 190.755 4.390 ;
        RECT 191.645 3.500 191.875 4.160 ;
        RECT 192.765 3.875 192.995 4.390 ;
        RECT 193.885 3.500 194.115 4.160 ;
        RECT 195.005 3.875 195.360 4.390 ;
        RECT 196.125 3.500 196.355 4.160 ;
        RECT 197.245 4.065 217.635 4.710 ;
        RECT 197.245 3.875 197.505 4.065 ;
        RECT 199.485 3.875 199.715 4.065 ;
        RECT 201.725 3.875 201.955 4.065 ;
        RECT 203.965 3.875 204.195 4.065 ;
        RECT 206.205 3.875 206.435 4.065 ;
        RECT 208.445 3.875 208.675 4.065 ;
        RECT 210.685 3.875 210.915 4.065 ;
        RECT 212.925 3.875 213.155 4.065 ;
        RECT 215.165 3.875 215.395 4.065 ;
        RECT 217.405 3.875 217.635 4.065 ;
        RECT 198.310 3.500 198.650 3.835 ;
        RECT 200.550 3.500 200.890 3.835 ;
        RECT 202.790 3.500 203.130 3.835 ;
        RECT 205.030 3.500 205.370 3.835 ;
        RECT 207.270 3.500 207.610 3.835 ;
        RECT 209.510 3.500 209.850 3.835 ;
        RECT 211.750 3.500 212.090 3.835 ;
        RECT 213.990 3.500 214.330 3.835 ;
        RECT 216.230 3.500 216.570 3.835 ;
        RECT 218.525 3.500 218.755 4.360 ;
        RECT 219.790 4.000 220.130 4.385 ;
        RECT 219.400 3.500 226.220 4.000 ;
        RECT 183.560 2.900 226.220 3.500 ;
        RECT 219.400 2.400 226.220 2.900 ;
      LAYER Via1 ;
        RECT 1.580 152.880 1.840 153.140 ;
        RECT 154.430 152.880 154.690 153.140 ;
        RECT 152.240 151.980 152.500 152.240 ;
        RECT 154.430 151.980 154.690 152.240 ;
        RECT 1.580 148.880 1.840 149.140 ;
        RECT 152.240 147.980 152.500 148.240 ;
        RECT 1.580 144.880 1.840 145.140 ;
        RECT 152.240 143.980 152.500 144.240 ;
        RECT 1.580 140.880 1.840 141.140 ;
        RECT 152.240 139.980 152.500 140.240 ;
        RECT 1.580 136.880 1.840 137.140 ;
        RECT 152.240 135.980 152.500 136.240 ;
        RECT 1.580 132.880 1.840 133.140 ;
        RECT 152.240 131.980 152.500 132.240 ;
        RECT 1.580 128.880 1.840 129.140 ;
        RECT 152.240 127.980 152.500 128.240 ;
        RECT 1.580 124.880 1.840 125.140 ;
        RECT 152.240 123.980 152.500 124.240 ;
        RECT 1.580 120.880 1.840 121.140 ;
        RECT 152.240 119.980 152.500 120.240 ;
        RECT 1.580 116.880 1.840 117.140 ;
        RECT 152.240 115.980 152.500 116.240 ;
        RECT 1.580 112.880 1.840 113.140 ;
        RECT 152.240 111.980 152.500 112.240 ;
        RECT 1.580 108.880 1.840 109.140 ;
        RECT 152.240 107.980 152.500 108.240 ;
        RECT 1.580 104.880 1.840 105.140 ;
        RECT 152.240 103.980 152.500 104.240 ;
        RECT 1.580 100.880 1.840 101.140 ;
        RECT 152.240 99.980 152.500 100.240 ;
        RECT 1.580 96.880 1.840 97.140 ;
        RECT 152.240 95.980 152.500 96.240 ;
        RECT 1.580 92.880 1.840 93.140 ;
        RECT 152.240 91.980 152.500 92.240 ;
        RECT 1.580 88.880 1.840 89.140 ;
        RECT 152.240 87.980 152.500 88.240 ;
        RECT 1.580 84.880 1.840 85.140 ;
        RECT 152.240 83.980 152.500 84.240 ;
        RECT 162.430 148.880 162.690 149.140 ;
        RECT 161.430 140.880 161.690 141.140 ;
        RECT 160.430 132.880 160.690 133.140 ;
        RECT 159.430 124.880 159.690 125.140 ;
        RECT 158.430 116.880 158.690 117.140 ;
        RECT 157.430 108.880 157.690 109.140 ;
        RECT 156.430 100.880 156.690 101.140 ;
        RECT 154.430 83.980 154.690 84.240 ;
        RECT 1.580 80.880 1.840 81.140 ;
        RECT 154.430 80.880 154.690 81.140 ;
        RECT 152.240 79.980 152.500 80.240 ;
        RECT 154.430 79.980 154.690 80.240 ;
        RECT 1.580 76.880 1.840 77.140 ;
        RECT 154.430 76.880 154.690 77.140 ;
        RECT 150.600 75.980 150.860 76.240 ;
        RECT 154.430 75.980 154.690 76.240 ;
        RECT 1.580 72.880 1.840 73.140 ;
        RECT 150.600 71.980 150.860 72.240 ;
        RECT 1.580 68.880 1.840 69.140 ;
        RECT 150.600 67.980 150.860 68.240 ;
        RECT 1.580 64.880 1.840 65.140 ;
        RECT 150.600 63.980 150.860 64.240 ;
        RECT 1.580 60.880 1.840 61.140 ;
        RECT 150.600 59.980 150.860 60.240 ;
        RECT 1.580 56.880 1.840 57.140 ;
        RECT 150.600 55.980 150.860 56.240 ;
        RECT 1.580 52.880 1.840 53.140 ;
        RECT 150.600 51.980 150.860 52.240 ;
        RECT 1.580 48.880 1.840 49.140 ;
        RECT 150.600 47.980 150.860 48.240 ;
        RECT 1.580 44.880 1.840 45.140 ;
        RECT 150.600 43.980 150.860 44.240 ;
        RECT 1.580 40.880 1.840 41.140 ;
        RECT 154.430 40.880 154.690 41.140 ;
        RECT 150.600 39.980 150.860 40.240 ;
        RECT 154.430 39.980 154.690 40.240 ;
        RECT 0.210 0.210 0.470 0.990 ;
        RECT 155.430 92.880 155.690 93.140 ;
        RECT 177.430 147.980 177.690 148.240 ;
        RECT 176.430 143.980 176.690 144.240 ;
        RECT 175.430 139.980 175.690 140.240 ;
        RECT 174.430 135.980 174.690 136.240 ;
        RECT 173.430 131.980 173.690 132.240 ;
        RECT 172.430 127.980 172.690 128.240 ;
        RECT 171.430 123.980 171.690 124.240 ;
        RECT 170.430 119.980 170.690 120.240 ;
        RECT 169.430 115.980 169.690 116.240 ;
        RECT 168.430 111.980 168.690 112.240 ;
        RECT 167.430 107.980 167.690 108.240 ;
        RECT 166.430 103.980 166.690 104.240 ;
        RECT 165.430 99.980 165.690 100.240 ;
        RECT 164.430 95.980 164.690 96.240 ;
        RECT 163.430 91.980 163.690 92.240 ;
        RECT 164.430 88.880 164.690 89.140 ;
        RECT 166.430 96.880 166.690 97.140 ;
        RECT 168.430 104.880 168.690 105.140 ;
        RECT 170.430 112.880 170.690 113.140 ;
        RECT 172.430 120.880 172.690 121.140 ;
        RECT 174.430 128.880 174.690 129.140 ;
        RECT 176.430 136.880 176.690 137.140 ;
        RECT 178.430 144.880 178.690 145.140 ;
        RECT 220.990 144.880 221.250 145.140 ;
        RECT 225.390 144.880 225.650 145.140 ;
        RECT 179.430 87.980 179.690 88.240 ;
        RECT 179.430 84.880 179.690 85.140 ;
        RECT 178.430 72.880 178.690 73.140 ;
        RECT 177.430 71.980 177.690 72.240 ;
        RECT 176.430 68.880 176.690 69.140 ;
        RECT 175.430 67.980 175.690 68.240 ;
        RECT 174.430 64.880 174.690 65.140 ;
        RECT 173.430 63.980 173.690 64.240 ;
        RECT 172.430 60.880 172.690 61.140 ;
        RECT 171.430 59.980 171.690 60.240 ;
        RECT 170.430 56.880 170.690 57.140 ;
        RECT 169.430 55.980 169.690 56.240 ;
        RECT 168.430 52.880 168.690 53.140 ;
        RECT 167.430 51.980 167.690 52.240 ;
        RECT 166.430 48.880 166.690 49.140 ;
        RECT 165.430 47.980 165.690 48.240 ;
        RECT 164.430 44.880 164.690 45.140 ;
        RECT 163.430 43.980 163.690 44.240 ;
        RECT 162.430 33.330 162.690 33.590 ;
        RECT 205.670 33.330 207.490 33.590 ;
        RECT 221.050 33.910 225.990 35.210 ;
        RECT 194.050 32.485 194.310 32.745 ;
        RECT 220.990 32.485 221.250 32.745 ;
        RECT 225.390 32.485 225.650 32.745 ;
        RECT 194.050 28.535 194.310 28.795 ;
        RECT 221.050 29.990 225.990 31.290 ;
        RECT 220.990 28.535 221.250 28.795 ;
        RECT 225.390 28.535 225.650 28.795 ;
        RECT 161.430 27.690 161.690 27.950 ;
        RECT 205.670 27.690 207.490 27.950 ;
        RECT 160.430 25.490 160.690 25.750 ;
        RECT 205.670 25.490 207.490 25.750 ;
        RECT 221.050 26.070 225.990 27.370 ;
        RECT 194.050 24.645 194.310 24.905 ;
        RECT 220.990 24.645 221.250 24.905 ;
        RECT 225.390 24.645 225.650 24.905 ;
        RECT 194.050 20.695 194.310 20.955 ;
        RECT 221.050 22.150 225.990 23.450 ;
        RECT 220.990 20.695 221.250 20.955 ;
        RECT 225.390 20.695 225.650 20.955 ;
        RECT 159.430 19.850 159.690 20.110 ;
        RECT 205.670 19.850 207.490 20.110 ;
        RECT 158.430 17.650 158.690 17.910 ;
        RECT 205.670 17.650 207.490 17.910 ;
        RECT 221.050 18.230 225.990 19.530 ;
        RECT 194.050 16.805 194.310 17.065 ;
        RECT 220.990 16.805 221.250 17.065 ;
        RECT 225.390 16.805 225.650 17.065 ;
        RECT 194.050 12.855 194.310 13.115 ;
        RECT 221.050 14.310 225.990 15.610 ;
        RECT 220.990 12.855 221.250 13.115 ;
        RECT 225.390 12.855 225.650 13.115 ;
        RECT 157.430 12.010 157.690 12.270 ;
        RECT 205.670 12.010 207.490 12.270 ;
        RECT 156.430 9.810 156.690 10.070 ;
        RECT 205.670 9.810 207.490 10.070 ;
        RECT 221.050 10.390 225.990 11.690 ;
        RECT 194.050 8.965 194.310 9.225 ;
        RECT 220.990 8.965 221.250 9.225 ;
        RECT 225.390 8.965 225.650 9.225 ;
        RECT 194.050 5.015 194.310 5.275 ;
        RECT 221.050 6.470 225.990 7.770 ;
        RECT 220.990 5.015 221.250 5.275 ;
        RECT 225.390 5.015 225.650 5.275 ;
        RECT 155.430 4.170 155.690 4.430 ;
        RECT 205.670 4.170 207.490 4.430 ;
        RECT 221.050 2.550 225.990 3.850 ;
        RECT 154.430 0.210 154.690 0.990 ;
      LAYER Metal2 ;
        RECT 1.510 152.810 154.760 153.210 ;
        RECT 152.170 151.910 154.760 152.310 ;
        RECT 1.510 148.810 162.760 149.210 ;
        RECT 152.170 147.910 177.760 148.310 ;
        RECT 1.510 144.810 221.320 145.210 ;
        RECT 152.170 143.910 176.760 144.310 ;
        RECT 1.510 140.810 161.760 141.210 ;
        RECT 152.170 139.910 175.760 140.310 ;
        RECT 1.510 136.810 176.760 137.210 ;
        RECT 152.170 135.910 174.760 136.310 ;
        RECT 1.510 132.810 160.760 133.210 ;
        RECT 152.170 131.910 173.760 132.310 ;
        RECT 1.510 128.810 174.760 129.210 ;
        RECT 152.170 127.910 172.760 128.310 ;
        RECT 1.510 124.810 159.760 125.210 ;
        RECT 152.170 123.910 171.760 124.310 ;
        RECT 1.510 120.810 172.760 121.210 ;
        RECT 152.170 119.910 170.760 120.310 ;
        RECT 1.510 116.810 158.760 117.210 ;
        RECT 152.170 115.910 169.760 116.310 ;
        RECT 1.510 112.810 170.760 113.210 ;
        RECT 152.170 111.910 168.760 112.310 ;
        RECT 1.510 108.810 157.760 109.210 ;
        RECT 152.170 107.910 167.760 108.310 ;
        RECT 1.510 104.810 168.760 105.210 ;
        RECT 152.170 103.910 166.760 104.310 ;
        RECT 1.510 100.810 156.760 101.210 ;
        RECT 152.170 99.910 165.760 100.310 ;
        RECT 1.510 96.810 166.760 97.210 ;
        RECT 152.170 95.910 164.760 96.310 ;
        RECT 1.510 92.810 155.760 93.210 ;
        RECT 152.170 91.910 163.760 92.310 ;
        RECT 1.510 88.810 164.760 89.210 ;
        RECT 152.170 87.910 179.760 88.310 ;
        RECT 1.510 84.810 179.760 85.210 ;
        RECT 152.170 83.910 154.760 84.310 ;
        RECT 1.510 80.810 154.760 81.210 ;
        RECT 152.170 79.910 154.760 80.310 ;
        RECT 1.510 76.810 154.760 77.210 ;
        RECT 150.530 75.910 154.760 76.310 ;
        RECT 1.510 72.810 178.760 73.210 ;
        RECT 150.530 71.910 177.760 72.310 ;
        RECT 1.510 68.810 176.760 69.210 ;
        RECT 150.530 67.910 175.760 68.310 ;
        RECT 1.510 64.810 174.760 65.210 ;
        RECT 150.530 63.910 173.760 64.310 ;
        RECT 1.510 60.810 172.760 61.210 ;
        RECT 150.530 59.910 171.760 60.310 ;
        RECT 1.510 56.810 170.760 57.210 ;
        RECT 150.530 55.910 169.760 56.310 ;
        RECT 1.510 52.810 168.760 53.210 ;
        RECT 150.530 51.910 167.760 52.310 ;
        RECT 1.510 48.810 166.760 49.210 ;
        RECT 150.530 47.910 165.760 48.310 ;
        RECT 1.510 44.810 164.760 45.210 ;
        RECT 150.530 43.910 163.760 44.310 ;
        RECT 1.510 40.810 154.760 41.210 ;
        RECT 150.530 39.910 154.760 40.310 ;
        RECT 220.820 33.760 226.220 35.360 ;
        RECT 162.360 33.260 207.560 33.660 ;
        RECT 193.980 32.415 221.320 32.815 ;
        RECT 220.820 29.840 226.220 31.440 ;
        RECT 193.980 28.465 221.320 28.865 ;
        RECT 161.360 27.620 207.560 28.020 ;
        RECT 220.820 25.920 226.220 27.520 ;
        RECT 160.360 25.420 207.560 25.820 ;
        RECT 193.980 24.575 221.320 24.975 ;
        RECT 220.820 22.000 226.220 23.600 ;
        RECT 193.980 20.625 221.320 21.025 ;
        RECT 159.360 19.780 207.560 20.180 ;
        RECT 220.820 18.080 226.220 19.680 ;
        RECT 158.360 17.580 207.560 17.980 ;
        RECT 193.980 16.735 221.320 17.135 ;
        RECT 220.820 14.160 226.220 15.760 ;
        RECT 193.980 12.785 221.320 13.185 ;
        RECT 157.360 11.940 207.560 12.340 ;
        RECT 220.820 10.240 226.220 11.840 ;
        RECT 156.360 9.740 207.560 10.140 ;
        RECT 193.980 8.895 221.320 9.295 ;
        RECT 220.820 6.320 226.220 7.920 ;
        RECT 193.980 4.945 221.320 5.345 ;
        RECT 155.360 4.100 207.560 4.500 ;
        RECT 220.820 2.400 226.220 4.000 ;
        RECT 0.140 0.000 0.540 1.200 ;
        RECT 154.360 0.000 154.760 1.200 ;
      LAYER Via2 ;
        RECT 223.690 33.900 226.050 35.220 ;
        RECT 221.100 29.980 222.940 31.300 ;
        RECT 223.690 26.060 226.050 27.380 ;
        RECT 221.100 22.140 222.940 23.460 ;
        RECT 223.690 18.220 226.050 19.540 ;
        RECT 221.100 14.300 222.940 15.620 ;
        RECT 223.690 10.380 226.050 11.700 ;
        RECT 221.100 6.460 222.940 7.780 ;
        RECT 223.690 2.540 226.050 3.860 ;
        RECT 0.200 0.200 0.480 1.000 ;
        RECT 154.420 0.200 154.700 1.000 ;
  END
END r2r_dac_analog
END LIBRARY

